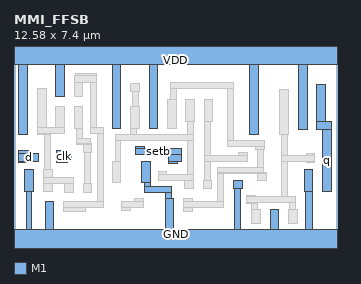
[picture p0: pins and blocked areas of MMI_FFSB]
MACRO MMI_FFSB
	CLASS CORE ;
	FOREIGN MMI_FFSB 0 0 ;
	SIZE 12.58 BY 7.4 ;
	SYMMETRY X Y ;
	SITE CORE1 ;
	PIN d
		DIRECTION input ;
		USE SIGNAL ;
		PORT
			LAYER M1 ;
			RECT 0.19 3.465 0.64 3.555 ;
			LAYER M1 ;
			RECT 0.19 3.125 0.95 3.465 ;
			LAYER M1 ;
			RECT 0.19 3.105 0.64 3.125 ;
		END
		AntennaGateArea 0.4968 ;
	END d
	PIN GND
		DIRECTION inout ;
		USE GROUND ;
		PORT
			LAYER M1 ;
			RECT 0.42 1.97 0.76 2.81 ;
			LAYER M1 ;
			RECT 4.975 2.31 5.315 3.15 ;
			LAYER M1 ;
			RECT 5.085 2.165 5.315 2.31 ;
			LAYER M1 ;
			RECT 0.47 0.5 0.7 1.97 ;
			LAYER M1 ;
			RECT 5.085 1.935 6.12 2.165 ;
			LAYER M1 ;
			RECT 8.555 2.065 8.895 2.405 ;
			LAYER M1 ;
			RECT 5.89 1.705 6.12 1.935 ;
			LAYER M1 ;
			RECT 1.21 0.5 1.55 1.57 ;
			LAYER M1 ;
			RECT 5.89 0.5 6.23 1.705 ;
			LAYER M1 ;
			RECT 8.575 0.5 8.805 2.065 ;
			LAYER M1 ;
			RECT 11.3 1.965 11.64 2.805 ;
			LAYER M1 ;
			RECT 9.98 0.5 10.32 1.275 ;
			LAYER M1 ;
			RECT 11.36 0.5 11.64 1.965 ;
			LAYER M1 ;
			RECT 0 -0.5 12.58 0.5 ;
		END
	END GND
	PIN q
		DIRECTION output ;
		USE SIGNAL ;
		PORT
			LAYER M1 ;
			RECT 11.795 4.71 12.135 6.13 ;
			LAYER M1 ;
			RECT 11.795 4.37 12.36 4.71 ;
			LAYER M1 ;
			RECT 12.02 1.965 12.36 4.37 ;
		END
		AntennaDiffArea 1.3248 ;
	END q
	PIN VDD
		DIRECTION inout ;
		USE POWER ;
		PORT
			LAYER M1 ;
			RECT 0 6.9 12.58 7.9 ;
			LAYER M1 ;
			RECT 0.19 4.2 0.53 6.9 ;
			LAYER M1 ;
			RECT 1.515 6.895 1.96 6.9 ;
			LAYER M1 ;
			RECT 1.62 5.655 1.96 6.895 ;
			LAYER M1 ;
			RECT 3.825 4.43 4.165 6.9 ;
			LAYER M1 ;
			RECT 5.265 4.43 5.605 6.9 ;
			LAYER M1 ;
			RECT 9.185 4.185 9.525 6.9 ;
			LAYER M1 ;
			RECT 11.075 4.37 11.415 6.9 ;
		END
	END VDD
	PIN setb
		DIRECTION input ;
		USE SIGNAL ;
		PORT
			LAYER M1 ;
			RECT 4.745 3.64 5.085 3.735 ;
			LAYER M1 ;
			RECT 4.745 3.41 6.515 3.64 ;
			LAYER M1 ;
			RECT 4.745 3.395 5.085 3.41 ;
			LAYER M1 ;
			RECT 6.015 3.125 6.515 3.41 ;
			LAYER M1 ;
			RECT 6.015 3.075 6.355 3.125 ;
		END
		AntennaGateArea 0.6552 ;
	END setb
	PIN clk
		DIRECTION input ;
		USE CLOCK ;
		PORT
			LAYER M1 ;
			RECT 1.64 3.495 2.09 3.555 ;
			LAYER M1 ;
			RECT 1.64 3.155 2.235 3.495 ;
			LAYER M1 ;
			RECT 1.64 3.105 2.09 3.155 ;
		END
		AntennaGateArea 0.6408 ;
	END clk
	OBS
		LAYER M1 ;
		RECT 0.91 4.47 1.25 5.96 ;
		LAYER M1 ;
		RECT 2.39 6.495 3.215 6.555 ;
		LAYER M1 ;
		RECT 2.34 6.215 3.215 6.495 ;
		LAYER M1 ;
		RECT 2.34 5.655 2.68 6.215 ;
		LAYER M1 ;
		RECT 1.62 4.47 1.96 5.27 ;
		LAYER M1 ;
		RECT 0.91 4.24 1.96 4.47 ;
		LAYER M1 ;
		RECT 2.34 4.43 2.68 5.27 ;
		LAYER M1 ;
		RECT 0.91 4.2 1.41 4.24 ;
		LAYER M1 ;
		RECT 1.18 2.81 1.41 4.2 ;
		LAYER M1 ;
		RECT 2.45 4.015 2.68 4.43 ;
		LAYER M1 ;
		RECT 2.985 4.475 3.215 6.215 ;
		LAYER M1 ;
		RECT 2.985 4.245 3.49 4.475 ;
		LAYER M1 ;
		RECT 4.555 5.85 4.895 6.19 ;
		LAYER M1 ;
		RECT 4.61 5.27 4.84 5.85 ;
		LAYER M1 ;
		RECT 4.545 4.43 4.885 5.27 ;
		LAYER M1 ;
		RECT 6.095 5.98 8.55 6.21 ;
		LAYER M1 ;
		RECT 6.095 5.55 6.325 5.98 ;
		LAYER M1 ;
		RECT 5.985 4.43 6.325 5.55 ;
		LAYER M1 ;
		RECT 6.685 4.695 7.025 5.535 ;
		LAYER M1 ;
		RECT 7.405 4.695 7.745 5.535 ;
		LAYER M1 ;
		RECT 2.45 3.82 2.965 4.015 ;
		LAYER M1 ;
		RECT 2.45 3.785 3.03 3.82 ;
		LAYER M1 ;
		RECT 2.69 3.48 3.03 3.785 ;
		LAYER M1 ;
		RECT 1.14 2.5 1.48 2.81 ;
		LAYER M1 ;
		RECT 1.13 2.27 2.31 2.5 ;
		LAYER M1 ;
		RECT 2.735 2.27 2.965 3.48 ;
		LAYER M1 ;
		RECT 1.14 1.97 1.48 2.27 ;
		LAYER M1 ;
		RECT 1.97 1.93 2.31 2.27 ;
		LAYER M1 ;
		RECT 2.69 1.93 3.03 2.27 ;
		LAYER M1 ;
		RECT 3.26 1.57 3.49 4.245 ;
		LAYER M1 ;
		RECT 4.545 4.195 4.775 4.43 ;
		LAYER M1 ;
		RECT 6.75 4.195 6.98 4.695 ;
		LAYER M1 ;
		RECT 3.935 3.965 6.98 4.195 ;
		LAYER M1 ;
		RECT 3.935 3.15 4.165 3.965 ;
		LAYER M1 ;
		RECT 3.825 2.31 4.165 3.15 ;
		LAYER M1 ;
		RECT 5.61 2.635 5.95 2.735 ;
		LAYER M1 ;
		RECT 6.75 2.635 6.98 3.965 ;
		LAYER M1 ;
		RECT 5.61 2.405 6.98 2.635 ;
		LAYER M1 ;
		RECT 7.41 3.375 7.64 4.695 ;
		LAYER M1 ;
		RECT 8.32 3.95 8.55 5.98 ;
		LAYER M1 ;
		RECT 10.335 4.18 10.675 5.94 ;
		LAYER M1 ;
		RECT 8.32 3.72 9.765 3.95 ;
		LAYER M1 ;
		RECT 9.425 3.61 9.765 3.72 ;
		LAYER M1 ;
		RECT 8.755 3.375 9.095 3.47 ;
		LAYER M1 ;
		RECT 7.41 3.145 9.095 3.375 ;
		LAYER M1 ;
		RECT 7.41 2.405 7.64 3.145 ;
		LAYER M1 ;
		RECT 8.755 3.13 9.095 3.145 ;
		LAYER M1 ;
		RECT 9.475 2.895 9.705 3.61 ;
		LAYER M1 ;
		RECT 7.94 2.725 9.705 2.895 ;
		LAYER M1 ;
		RECT 10.435 3.375 10.665 4.18 ;
		LAYER M1 ;
		RECT 11.375 3.375 11.715 3.445 ;
		LAYER M1 ;
		RECT 10.435 3.145 11.715 3.375 ;
		LAYER M1 ;
		RECT 7.94 2.665 9.815 2.725 ;
		LAYER M1 ;
		RECT 5.61 2.395 5.95 2.405 ;
		LAYER M1 ;
		RECT 6.65 2.065 6.99 2.405 ;
		LAYER M1 ;
		RECT 7.37 2.065 7.71 2.405 ;
		LAYER M1 ;
		RECT 1.93 1.34 3.49 1.57 ;
		LAYER M1 ;
		RECT 4.7 1.565 5.04 1.705 ;
		LAYER M1 ;
		RECT 1.93 1.19 2.79 1.34 ;
		LAYER M1 ;
		RECT 4.18 1.335 5.04 1.565 ;
		LAYER M1 ;
		RECT 4.18 1.225 4.52 1.335 ;
		LAYER M1 ;
		RECT 6.61 1.575 6.95 1.705 ;
		LAYER M1 ;
		RECT 7.94 1.575 8.17 2.665 ;
		LAYER M1 ;
		RECT 9.475 2.385 9.815 2.665 ;
		LAYER M1 ;
		RECT 6.61 1.345 8.175 1.575 ;
		LAYER M1 ;
		RECT 6.61 1.185 6.95 1.345 ;
		LAYER M1 ;
		RECT 9.065 1.755 9.405 1.83 ;
		LAYER M1 ;
		RECT 10.435 1.755 10.665 3.145 ;
		LAYER M1 ;
		RECT 11.375 3.105 11.715 3.145 ;
		LAYER M1 ;
		RECT 9.065 1.525 10.95 1.755 ;
		LAYER M1 ;
		RECT 9.065 1.49 9.49 1.525 ;
		LAYER M1 ;
		RECT 9.26 1.275 9.49 1.49 ;
		LAYER M1 ;
		RECT 10.72 1.275 10.95 1.525 ;
		LAYER M1 ;
		RECT 9.26 0.735 9.6 1.275 ;
		LAYER M1 ;
		RECT 10.7 0.735 11.04 1.275 ;
	END
END MMI_FFSB
